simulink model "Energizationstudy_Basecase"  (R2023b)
settings: Solver=ode15s  StartTime=0.0  StopTime=120  RelTol=1e-3
PreLoadFcn:
  | Ts=50e-6;
undefined symbols (not defined in the file or in its folder): DiscIntNeverNeededParam, find_system, Ion, Lithium
libraries: spsThreePhaseVIMeasurementLib x9, spsabctodq0Lib x6, spsThreePhaseBreakerLib x6, slpidlib x4, spsFirstOrderFilterLib x3, spsPower3phInstantaneousLib x3, spsThreePhaseSeriesRLCBranchLib x2, simulink_extras x2, simulink x2, spsStairGeneratorLib x2, spsThreePhaseSeriesRLCLoadLib x2, spsThreePhaseTransformerTwoWindingsLib x2
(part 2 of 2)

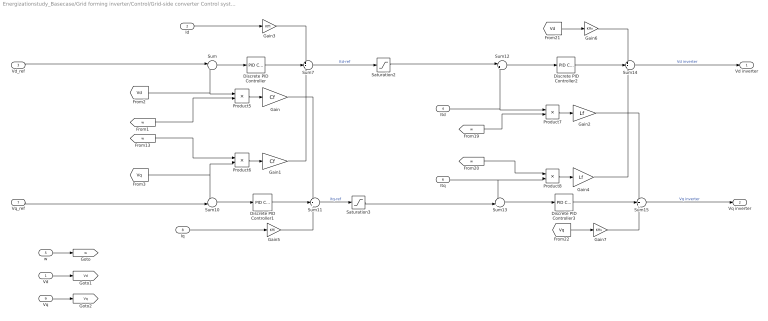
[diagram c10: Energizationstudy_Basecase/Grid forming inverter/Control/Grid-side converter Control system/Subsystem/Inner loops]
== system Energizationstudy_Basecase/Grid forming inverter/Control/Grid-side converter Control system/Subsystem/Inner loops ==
  Vd : Inport
  Id : Inport  Port=2
  Vd_ref : Inport  Port=3
  Itd : Inport  Port=4
  w : Inport  Port=5
  Itq : Inport  Port=6
  Vq_ref : Inport  Port=7
  Iq : Inport  Port=8
  Vq : Inport  Port=9
  Discrete PID Controller : slpidlib/PID Controller  Controller=PI  Form=Parallel  TimeDomain=Discrete-time  UseExternalTs=off  SampleTime=Ts  IntegratorMethod=Forward Euler  FilterMethod=Forward Euler  ControllerParametersSource=internal  P=Kp_vc  I=Ki_vc  UseKiTs=off  D=0  N=100  UseFilter=on  TunerSelectOption=Transfer Function Based (PID Tuner App)  InitialConditionSource=internal  InitialConditionForIntegrator=0  InitialConditionForFilter=0  DifferentiatorICPrevScaledInput=0  ExternalReset=none  TrackingMode=off  Kt=1  LimitOutput=off  SatLimitsSource=internal  UpperSaturationLimit=inf  LowerSaturationLimit=-inf  LinearizeAsGain=off  AntiWindupMode=none  Kb=1  LimitIntegrator=off  UpperIntegratorSaturationLimit=inf  LowerIntegratorSaturationLimit=-inf  POutMin=[]  POutMax=[]  IOutMin=[]  IOutMax=[]  DOutMin=[]  DOutMax=[]  NOutMin=[]  NOutMax=[]  SumOutMin=[]  SumOutMax=[]  SaturationOutMin=[]  SaturationOutMax=[]  PParamMin=[]  PParamMax=[]  IParamMin=[]  IParamMax=[]  DParamMin=[]  DParamMax=[]  NParamMin=[]  NParamMax=[]  KbParamMin=[]  KbParamMax=[]  KtParamMin=[]  KtParamMax=[]  KbOutMin=[]  KbOutMax=[]  KtOutMin=[]  KtOutMax=[]  IntegratorOutMin=[]  IntegratorOutMax=[]  FilterOutMin=[]  FilterOutMax=[]  SumI1OutMin=[]  SumI1OutMax=[]  SumI2OutMin=[]  SumI2OutMax=[]  SumI3OutMin=[]  SumI3OutMax=[]  SumI4OutMin=[]  SumI4OutMax=[]  SumDOutMin=[]  SumDOutMax=[]  DifferentiatorOutMin=[]  DifferentiatorOutMax=[]  FilterDiffOutCoefMin=[]  FilterDiffOutCoefMax=[]  ReciprocalOutMin=[]  ReciprocalOutMax=[]  SumDenOutMin=[]  SumDenOutMax=[]  SumNumOutMin=[]  SumNumOutMax=[]  DivideOutMin=[]  DivideOutMax=[]  UdiffTsProdOutMin=[]  UdiffTsProdOutMax=[]  NTsProdOutMin=[]  NTsProdOutMax=[]  UintegralTsProdOutMin=[]  UintegralTsProdOutMax=[]  UngainTsProdOutMin=[]  UngainTsProdOutMax=[]  ClampingZeroOutDataTypeStr=Inherit: Inherit via back propagation  ClampingZeroOutMin=[]  ClampingZeroOutMax=[]  FilterDenConstantOutDataTypeStr=Inherit: Inherit via back propagation  FilterDenConstantOutMin=[]  FilterDenConstantOutMax=[]  PCopyOutDataTypeStr=Inherit: Inherit via back propagation  PCopyOutMin=[]  PCopyOutMax=[]  NCopyOutDataTypeStr=Inherit: Inherit via back propagation  NCopyOutMin=[]  NCopyOutMax=[]  IntegratorContinuousStateAttributes=''  IntegratorStateMustResolveToSignalObject=off  IntegratorRTWStateStorageClass=Auto  FilterContinuousStateAttributes=''  FilterStateMustResolveToSignalObject=off  FilterRTWStateStorageClass=Auto  ParallelPVariant=InternalParameters  IdealPVariant=Disabled  IVariant=InternalParameters  DVariant=Disabled  IntegratorVariant=Discrete  SatVariant=Disabled  AWVariant=Passthrough  PCopyVariant=Disabled  TRVariant=Disabled  FdbkBlocksVariant=Forward  IdealPFdbkVariant=Disabled  SatFdbkVariant=Disabled  DerivativeFilterVariant=Disabled  NVariant=Disabled  NCopyVariant=Disabled_SignalSpec  FilterICVariant=Disabled  IntegratorICVariant=InternalICs  ExternalResetVariant=Disabled  TRSumVariant=Passthrough  SumFdbkVariant=Disabled  SumVariant=Sum_PI  TsampFilterVariant=InternalTs  TsampNgainVariant=Passthrough  TsampIntegralVariant=Disabled_SignalSpec  ExternalSaturationOutDataTypeStr=Inherit: Same as second input
  Discrete PID Controller1 : slpidlib/PID Controller  Controller=PI  Form=Parallel  TimeDomain=Discrete-time  UseExternalTs=off  SampleTime=Ts  IntegratorMethod=Forward Euler  FilterMethod=Forward Euler  ControllerParametersSource=internal  P=Kp_vc  I=Ki_vc  UseKiTs=off  D=0  N=100  UseFilter=on  TunerSelectOption=Transfer Function Based (PID Tuner App)  InitialConditionSource=internal  InitialConditionForIntegrator=0  InitialConditionForFilter=0  DifferentiatorICPrevScaledInput=0  ExternalReset=none  TrackingMode=off  Kt=1  LimitOutput=off  SatLimitsSource=internal  UpperSaturationLimit=inf  LowerSaturationLimit=-inf  LinearizeAsGain=off  AntiWindupMode=none  Kb=1  LimitIntegrator=off  UpperIntegratorSaturationLimit=inf  LowerIntegratorSaturationLimit=-inf  POutMin=[]  POutMax=[]  IOutMin=[]  IOutMax=[]  DOutMin=[]  DOutMax=[]  NOutMin=[]  NOutMax=[]  SumOutMin=[]  SumOutMax=[]  SaturationOutMin=[]  SaturationOutMax=[]  PParamMin=[]  PParamMax=[]  IParamMin=[]  IParamMax=[]  DParamMin=[]  DParamMax=[]  NParamMin=[]  NParamMax=[]  KbParamMin=[]  KbParamMax=[]  KtParamMin=[]  KtParamMax=[]  KbOutMin=[]  KbOutMax=[]  KtOutMin=[]  KtOutMax=[]  IntegratorOutMin=[]  IntegratorOutMax=[]  FilterOutMin=[]  FilterOutMax=[]  SumI1OutMin=[]  SumI1OutMax=[]  SumI2OutMin=[]  SumI2OutMax=[]  SumI3OutMin=[]  SumI3OutMax=[]  SumI4OutMin=[]  SumI4OutMax=[]  SumDOutMin=[]  SumDOutMax=[]  DifferentiatorOutMin=[]  DifferentiatorOutMax=[]  FilterDiffOutCoefMin=[]  FilterDiffOutCoefMax=[]  ReciprocalOutMin=[]  ReciprocalOutMax=[]  SumDenOutMin=[]  SumDenOutMax=[]  SumNumOutMin=[]  SumNumOutMax=[]  DivideOutMin=[]  DivideOutMax=[]  UdiffTsProdOutMin=[]  UdiffTsProdOutMax=[]  NTsProdOutMin=[]  NTsProdOutMax=[]  UintegralTsProdOutMin=[]  UintegralTsProdOutMax=[]  UngainTsProdOutMin=[]  UngainTsProdOutMax=[]  ClampingZeroOutDataTypeStr=Inherit: Inherit via back propagation  ClampingZeroOutMin=[]  ClampingZeroOutMax=[]  FilterDenConstantOutDataTypeStr=Inherit: Inherit via back propagation  FilterDenConstantOutMin=[]  FilterDenConstantOutMax=[]  PCopyOutDataTypeStr=Inherit: Inherit via back propagation  PCopyOutMin=[]  PCopyOutMax=[]  NCopyOutDataTypeStr=Inherit: Inherit via back propagation  NCopyOutMin=[]  NCopyOutMax=[]  IntegratorContinuousStateAttributes=''  IntegratorStateMustResolveToSignalObject=off  IntegratorRTWStateStorageClass=Auto  FilterContinuousStateAttributes=''  FilterStateMustResolveToSignalObject=off  FilterRTWStateStorageClass=Auto  ParallelPVariant=InternalParameters  IdealPVariant=Disabled  IVariant=InternalParameters  DVariant=Disabled  IntegratorVariant=Discrete  SatVariant=Disabled  AWVariant=Passthrough  PCopyVariant=Disabled  TRVariant=Disabled  FdbkBlocksVariant=Forward  IdealPFdbkVariant=Disabled  SatFdbkVariant=Disabled  DerivativeFilterVariant=Disabled  NVariant=Disabled  NCopyVariant=Disabled_SignalSpec  FilterICVariant=Disabled  IntegratorICVariant=InternalICs  ExternalResetVariant=Disabled  TRSumVariant=Passthrough  SumFdbkVariant=Disabled  SumVariant=Sum_PI  TsampFilterVariant=InternalTs  TsampNgainVariant=Passthrough  TsampIntegralVariant=Disabled_SignalSpec  ExternalSaturationOutDataTypeStr=Inherit: Same as second input
  Discrete PID Controller2 : slpidlib/PID Controller  Controller=PI  Form=Parallel  TimeDomain=Discrete-time  UseExternalTs=off  SampleTime=Ts  IntegratorMethod=Forward Euler  FilterMethod=Forward Euler  ControllerParametersSource=internal  P=Kp_cc  I=Ki_cc  UseKiTs=off  D=0  N=100  UseFilter=on  TunerSelectOption=Transfer Function Based (PID Tuner App)  InitialConditionSource=internal  InitialConditionForIntegrator=0  InitialConditionForFilter=0  DifferentiatorICPrevScaledInput=0  ExternalReset=none  TrackingMode=off  Kt=1  LimitOutput=off  SatLimitsSource=internal  UpperSaturationLimit=inf  LowerSaturationLimit=-inf  LinearizeAsGain=off  AntiWindupMode=none  Kb=1  LimitIntegrator=off  UpperIntegratorSaturationLimit=inf  LowerIntegratorSaturationLimit=-inf  POutMin=[]  POutMax=[]  IOutMin=[]  IOutMax=[]  DOutMin=[]  DOutMax=[]  NOutMin=[]  NOutMax=[]  SumOutMin=[]  SumOutMax=[]  SaturationOutMin=[]  SaturationOutMax=[]  PParamMin=[]  PParamMax=[]  IParamMin=[]  IParamMax=[]  DParamMin=[]  DParamMax=[]  NParamMin=[]  NParamMax=[]  KbParamMin=[]  KbParamMax=[]  KtParamMin=[]  KtParamMax=[]  KbOutMin=[]  KbOutMax=[]  KtOutMin=[]  KtOutMax=[]  IntegratorOutMin=[]  IntegratorOutMax=[]  FilterOutMin=[]  FilterOutMax=[]  SumI1OutMin=[]  SumI1OutMax=[]  SumI2OutMin=[]  SumI2OutMax=[]  SumI3OutMin=[]  SumI3OutMax=[]  SumI4OutMin=[]  SumI4OutMax=[]  SumDOutMin=[]  SumDOutMax=[]  DifferentiatorOutMin=[]  DifferentiatorOutMax=[]  FilterDiffOutCoefMin=[]  FilterDiffOutCoefMax=[]  ReciprocalOutMin=[]  ReciprocalOutMax=[]  SumDenOutMin=[]  SumDenOutMax=[]  SumNumOutMin=[]  SumNumOutMax=[]  DivideOutMin=[]  DivideOutMax=[]  UdiffTsProdOutMin=[]  UdiffTsProdOutMax=[]  NTsProdOutMin=[]  NTsProdOutMax=[]  UintegralTsProdOutMin=[]  UintegralTsProdOutMax=[]  UngainTsProdOutMin=[]  UngainTsProdOutMax=[]  ClampingZeroOutDataTypeStr=Inherit: Inherit via back propagation  ClampingZeroOutMin=[]  ClampingZeroOutMax=[]  FilterDenConstantOutDataTypeStr=Inherit: Inherit via back propagation  FilterDenConstantOutMin=[]  FilterDenConstantOutMax=[]  PCopyOutDataTypeStr=Inherit: Inherit via back propagation  PCopyOutMin=[]  PCopyOutMax=[]  NCopyOutDataTypeStr=Inherit: Inherit via back propagation  NCopyOutMin=[]  NCopyOutMax=[]  IntegratorContinuousStateAttributes=''  IntegratorStateMustResolveToSignalObject=off  IntegratorRTWStateStorageClass=Auto  FilterContinuousStateAttributes=''  FilterStateMustResolveToSignalObject=off  FilterRTWStateStorageClass=Auto  ParallelPVariant=InternalParameters  IdealPVariant=Disabled  IVariant=InternalParameters  DVariant=Disabled  IntegratorVariant=Discrete  SatVariant=Disabled  AWVariant=Passthrough  PCopyVariant=Disabled  TRVariant=Disabled  FdbkBlocksVariant=Forward  IdealPFdbkVariant=Disabled  SatFdbkVariant=Disabled  DerivativeFilterVariant=Disabled  NVariant=Disabled  NCopyVariant=Disabled_SignalSpec  FilterICVariant=Disabled  IntegratorICVariant=InternalICs  ExternalResetVariant=Disabled  TRSumVariant=Passthrough  SumFdbkVariant=Disabled  SumVariant=Sum_PI  TsampFilterVariant=InternalTs  TsampNgainVariant=Passthrough  TsampIntegralVariant=Disabled_SignalSpec  ExternalSaturationOutDataTypeStr=Inherit: Same as second input
  Discrete PID Controller3 : slpidlib/PID Controller  Controller=PI  Form=Parallel  TimeDomain=Discrete-time  UseExternalTs=off  SampleTime=Ts  IntegratorMethod=Forward Euler  FilterMethod=Forward Euler  ControllerParametersSource=internal  P=Kp_cc  I=Ki_cc  UseKiTs=off  D=0  N=100  UseFilter=on  TunerSelectOption=Transfer Function Based (PID Tuner App)  InitialConditionSource=internal  InitialConditionForIntegrator=0  InitialConditionForFilter=0  DifferentiatorICPrevScaledInput=0  ExternalReset=none  TrackingMode=off  Kt=1  LimitOutput=off  SatLimitsSource=internal  UpperSaturationLimit=inf  LowerSaturationLimit=-inf  LinearizeAsGain=off  AntiWindupMode=none  Kb=1  LimitIntegrator=off  UpperIntegratorSaturationLimit=inf  LowerIntegratorSaturationLimit=-inf  POutMin=[]  POutMax=[]  IOutMin=[]  IOutMax=[]  DOutMin=[]  DOutMax=[]  NOutMin=[]  NOutMax=[]  SumOutMin=[]  SumOutMax=[]  SaturationOutMin=[]  SaturationOutMax=[]  PParamMin=[]  PParamMax=[]  IParamMin=[]  IParamMax=[]  DParamMin=[]  DParamMax=[]  NParamMin=[]  NParamMax=[]  KbParamMin=[]  KbParamMax=[]  KtParamMin=[]  KtParamMax=[]  KbOutMin=[]  KbOutMax=[]  KtOutMin=[]  KtOutMax=[]  IntegratorOutMin=[]  IntegratorOutMax=[]  FilterOutMin=[]  FilterOutMax=[]  SumI1OutMin=[]  SumI1OutMax=[]  SumI2OutMin=[]  SumI2OutMax=[]  SumI3OutMin=[]  SumI3OutMax=[]  SumI4OutMin=[]  SumI4OutMax=[]  SumDOutMin=[]  SumDOutMax=[]  DifferentiatorOutMin=[]  DifferentiatorOutMax=[]  FilterDiffOutCoefMin=[]  FilterDiffOutCoefMax=[]  ReciprocalOutMin=[]  ReciprocalOutMax=[]  SumDenOutMin=[]  SumDenOutMax=[]  SumNumOutMin=[]  SumNumOutMax=[]  DivideOutMin=[]  DivideOutMax=[]  UdiffTsProdOutMin=[]  UdiffTsProdOutMax=[]  NTsProdOutMin=[]  NTsProdOutMax=[]  UintegralTsProdOutMin=[]  UintegralTsProdOutMax=[]  UngainTsProdOutMin=[]  UngainTsProdOutMax=[]  ClampingZeroOutDataTypeStr=Inherit: Inherit via back propagation  ClampingZeroOutMin=[]  ClampingZeroOutMax=[]  FilterDenConstantOutDataTypeStr=Inherit: Inherit via back propagation  FilterDenConstantOutMin=[]  FilterDenConstantOutMax=[]  PCopyOutDataTypeStr=Inherit: Inherit via back propagation  PCopyOutMin=[]  PCopyOutMax=[]  NCopyOutDataTypeStr=Inherit: Inherit via back propagation  NCopyOutMin=[]  NCopyOutMax=[]  IntegratorContinuousStateAttributes=''  IntegratorStateMustResolveToSignalObject=off  IntegratorRTWStateStorageClass=Auto  FilterContinuousStateAttributes=''  FilterStateMustResolveToSignalObject=off  FilterRTWStateStorageClass=Auto  ParallelPVariant=InternalParameters  IdealPVariant=Disabled  IVariant=InternalParameters  DVariant=Disabled  IntegratorVariant=Discrete  SatVariant=Disabled  AWVariant=Passthrough  PCopyVariant=Disabled  TRVariant=Disabled  FdbkBlocksVariant=Forward  IdealPFdbkVariant=Disabled  SatFdbkVariant=Disabled  DerivativeFilterVariant=Disabled  NVariant=Disabled  NCopyVariant=Disabled_SignalSpec  FilterICVariant=Disabled  IntegratorICVariant=InternalICs  ExternalResetVariant=Disabled  TRSumVariant=Passthrough  SumFdbkVariant=Disabled  SumVariant=Sum_PI  TsampFilterVariant=InternalTs  TsampNgainVariant=Passthrough  TsampIntegralVariant=Disabled_SignalSpec  ExternalSaturationOutDataTypeStr=Inherit: Same as second input
  Gain : Gain  Gain=Cf
  Gain1 : Gain  Gain=Cf
  Gain2 : Gain  Gain=Lf
  Gain3 : Gain  Gain=Kffi
  Gain4 : Gain  Gain=Lf
  Gain5 : Gain  Gain=Kffi
  Gain6 : Gain  Gain=Kffv
  Gain7 : Gain  Gain=Kffv
  Product{5..8} (4 alike) : Product
  Saturation2 : Saturate  UpperLimit=1.2*0.142*10e6  LowerLimit=-1.2*0.142*10e6  LinearizeAsGain=off  ZeroCross=off
  Saturation3 : Saturate  UpperLimit=1.2*0.106*10e6  LowerLimit=-1.2*0.106*10e6  LinearizeAsGain=off  ZeroCross=off
  Sum : Sum  Inputs=|+-
  Sum10 : Sum  Inputs=-+|
  Sum11 : Sum  Inputs=+++
  Sum12 : Sum  Inputs=|+-
  Sum13 : Sum  Inputs=-+|
  Sum14 : Sum  Inputs=++-
  Sum15 : Sum  Inputs=+++
  Sum7 : Sum  Inputs=++-
  Vd inverter : Outport
  Vq inverter : Outport  Port=2
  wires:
  [Vq] -> Sum10/1, Product6/2
  Itd/1 -> Sum12/2, Product7/1
  Sum/1 -> Discrete PID Controller/1
  [w] -> Product8/1
  Iq/1 -> Gain5/1
  Vd_ref/1 -> Sum/1
  [Vq] -> Gain7/1
  Gain2/1 -> Sum15/1
  [Vd] -> Gain6/1
  [Vd] -> Sum/2, Product5/1
  Product5/1 -> Gain/1
  [w] -> Product5/2
  Sum10/1 -> Discrete PID Controller1/1
  Gain3/1 -> Sum7/1
  Itq/1 -> Sum13/1, Product8/2
  Sum15/1 -> Vq inverter/1  "Vq inverter"
  [w] -> Product6/1
  Product6/1 -> Gain1/1
  Gain/1 -> Sum11/1
  [w] -> Product7/2
  Sum12/1 -> Discrete PID Controller2/1
  Vq_ref/1 -> Sum10/2
  Discrete PID Controller/1 -> Sum7/2
  Gain5/1 -> Sum11/3
  Gain4/1 -> Sum14/3
  Sum13/1 -> Discrete PID Controller3/1
  Gain1/1 -> Sum7/3
  Sum14/1 -> Vd inverter/1  "Vd inverter"
  Id/1 -> Gain3/1
  Product7/1 -> Gain2/1
  Product8/1 -> Gain4/1
  Discrete PID Controller2/1 -> Sum14/2
  Discrete PID Controller1/1 -> Sum11/2
  Gain6/1 -> Sum14/1
  Discrete PID Controller3/1 -> Sum15/2
  Gain7/1 -> Sum15/3
  w/1 -> [w]
  Vd/1 -> [Vd]
  Vq/1 -> [Vq]
  Sum7/1 -> Saturation2/1  "Itd-ref"
  Saturation2/1 -> Sum12/1
  Sum11/1 -> Saturation3/1  "itq-ref"
  Saturation3/1 -> Sum13/2

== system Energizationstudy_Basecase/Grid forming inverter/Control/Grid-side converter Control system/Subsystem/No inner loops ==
  Vd_ref : Inport
  Vq_ref : Inport  Port=2
  Vd inverter : Outport
  Vq inverter : Outport  Port=2
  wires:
  Vd_ref/1 -> Vd inverter/1
  Vq_ref/1 -> Vq inverter/1

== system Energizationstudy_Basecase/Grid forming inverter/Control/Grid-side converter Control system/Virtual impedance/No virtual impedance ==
  Vd_ref : Inport
  Vq_ref : Inport  Port=2
  Vd_ref* : Outport
  Vq_ref* : Outport  Port=2
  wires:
  Vd_ref/1 -> Vd_ref*/1
  Vq_ref/1 -> Vq_ref*/1

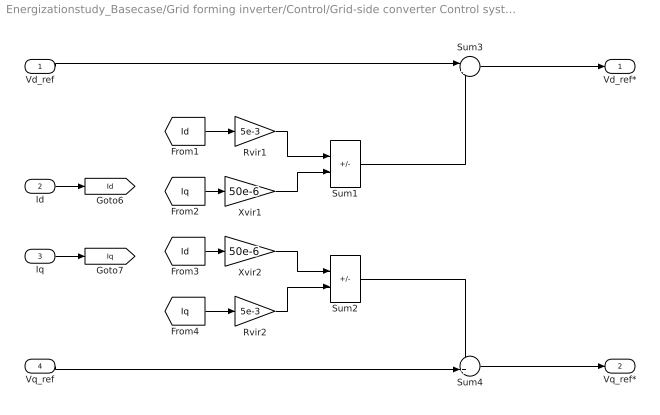
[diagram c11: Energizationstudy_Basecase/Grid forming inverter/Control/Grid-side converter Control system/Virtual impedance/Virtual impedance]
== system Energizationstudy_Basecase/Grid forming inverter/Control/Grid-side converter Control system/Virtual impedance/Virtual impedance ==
  Vd_ref : Inport
  Id : Inport  Port=2
  Iq : Inport  Port=3
  Vq_ref : Inport  Port=4
  Rvir1 : Gain  Gain=5e-3
  Rvir2 : Gain  Gain=5e-3
  Sum1 : Sum  Inputs=-+
  Sum2 : Sum  Inputs=--
  Sum3 : Sum  Inputs=|++
  Sum4 : Sum  Inputs=++|
  Xvir1 : Gain  Gain=50e-6
  Xvir2 : Gain  Gain=50e-6
  Vd_ref* : Outport
  Vq_ref* : Outport  Port=2
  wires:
  Sum2/1 -> Sum4/1
  Xvir1/1 -> Sum1/2
  Sum1/1 -> Sum3/2
  Sum3/1 -> Vd_ref*/1
  Rvir2/1 -> Sum2/2
  Xvir2/1 -> Sum2/1
  Rvir1/1 -> Sum1/1
  [Iq] -> Xvir1/1
  [Id] -> Xvir2/1
  Vq_ref/1 -> Sum4/2
  Sum4/1 -> Vq_ref*/1
  [Id] -> Rvir1/1
  [Iq] -> Rvir2/1
  Vd_ref/1 -> Sum3/1
  Id/1 -> [Id]
  Iq/1 -> [Iq]
